VERSION 5.8 ;
BUSBITCHARS "[]" ; DIVIDERCHAR "/" ;
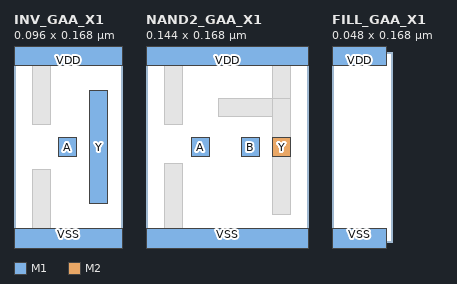
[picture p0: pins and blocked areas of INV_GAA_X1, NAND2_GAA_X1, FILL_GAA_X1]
MACRO INV_GAA_X1 CLASS CORE ; ORIGIN 0 0 ; FOREIGN INV_GAA_X1 0 0 ; SIZE 0.096 BY 0.168 ; SYMMETRY X Y ; SITE gaa3_core ;
  PIN A DIRECTION INPUT ; USE SIGNAL ; PORT LAYER M1 ; RECT 0.039 0.076 0.055 0.092 ; END END A
  PIN Y DIRECTION OUTPUT ; USE SIGNAL ; PORT LAYER M1 ; RECT 0.067 0.034 0.083 0.134 ; END END Y
  PIN VDD DIRECTION INOUT ; USE POWER ; PORT LAYER M1 ; RECT 0.000 0.156 0.096 0.180 ; END END VDD
  PIN VSS DIRECTION INOUT ; USE GROUND ; PORT LAYER M1 ; RECT 0.000 -0.012 0.096 0.012 ; END END VSS
  OBS LAYER M1 ; RECT 0.016 0.000 0.032 0.064 ; RECT 0.016 0.104 0.032 0.168 ; END
END INV_GAA_X1
MACRO NAND2_GAA_X1 CLASS CORE ; ORIGIN 0 0 ; FOREIGN NAND2_GAA_X1 0 0 ; SIZE 0.144 BY 0.168 ; SYMMETRY X Y ; SITE gaa3_core ;
  PIN A DIRECTION INPUT ; USE SIGNAL ; PORT LAYER M1 ; RECT 0.040 0.076 0.056 0.092 ; END END A
  PIN B DIRECTION INPUT ; USE SIGNAL ; PORT LAYER M1 ; RECT 0.084 0.076 0.100 0.092 ; END END B
  PIN Y DIRECTION OUTPUT ; USE SIGNAL ; PORT LAYER M2 ; RECT 0.112 0.076 0.128 0.092 ; END END Y
  PIN VDD DIRECTION INOUT ; USE POWER ; PORT LAYER M1 ; RECT 0.000 0.156 0.144 0.180 ; END END VDD
  PIN VSS DIRECTION INOUT ; USE GROUND ; PORT LAYER M1 ; RECT 0.000 -0.012 0.144 0.012 ; END END VSS
  OBS LAYER M1 ; RECT 0.016 0.000 0.032 0.069 ; RECT 0.016 0.104 0.032 0.168 ; RECT 0.112 0.024 0.128 0.092 ; RECT 0.112 0.104 0.128 0.168 ; LAYER M2 ; RECT 0.064 0.111 0.128 0.127 ; RECT 0.112 0.076 0.128 0.127 ; END
END NAND2_GAA_X1
MACRO FILL_GAA_X1 CLASS CORE SPACER ; ORIGIN 0 0 ; FOREIGN FILL_GAA_X1 0 0 ; SIZE 0.048 BY 0.168 ; SYMMETRY X Y ; SITE gaa3_core ;
  PIN VDD DIRECTION INOUT ; USE POWER ; PORT LAYER M1 ; RECT 0.000 0.156 0.048 0.180 ; END END VDD
  PIN VSS DIRECTION INOUT ; USE GROUND ; PORT LAYER M1 ; RECT 0.000 -0.012 0.048 0.012 ; END END VSS
END FILL_GAA_X1
END LIBRARY
